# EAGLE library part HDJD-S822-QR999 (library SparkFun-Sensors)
Avago RGB color sensor, analog out

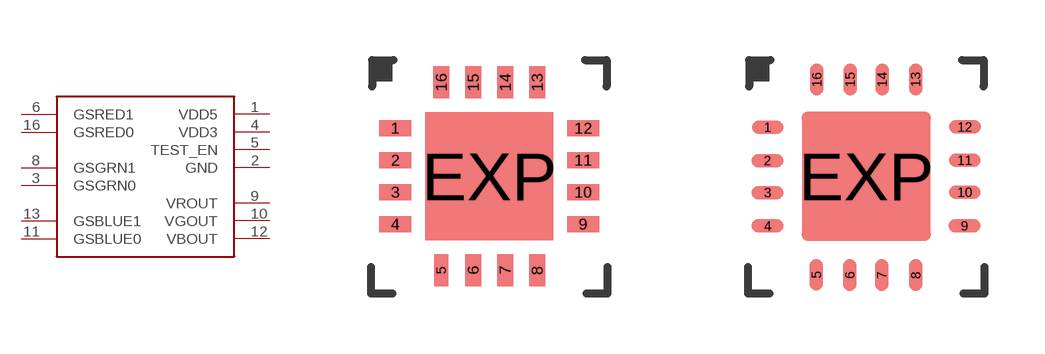
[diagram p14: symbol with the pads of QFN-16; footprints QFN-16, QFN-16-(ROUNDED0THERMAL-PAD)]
Designator prefix -

## HDJD-S822-QR999  [QFN-16]
1  VDD5
2  GND
3  GSGRN0
4  VDD3
5  TEST_EN
6  GSRED1
8  GSGRN1
9  VROUT
10  VGOUT
11  GSBLUE0
12  VBOUT
13  GSBLUE1
16  GSRED0

## HDJD-S822-QR999WITHPIC  [QFN-16-(ROUNDED0THERMAL-PAD)]
Pads as for QFN-16

## Footprint QFN-16 (pad centres in mm)
smd 0.8 x 0.4: 1 -2.35,1.2; 2 -2.35,0.4; 3 -2.35,-0.4; 4 -2.35,-1.2; 9 2.35,-1.2; 10 2.35,-0.4; 11 2.35,0.4; 12 2.35,1.2
smd 0.35 x 0.8: 5 -1.2,-2.35
smd 0.4 x 0.8: 6 -0.4,-2.35; 7 0.4,-2.35; 8 1.2,-2.35; 13 1.2,2.35; 14 0.4,2.35; 15 -0.4,2.35; 16 -1.2,2.35
smd 3.19 x 3.19: EXP 0,0

## Footprint QFN-16-(ROUNDED0THERMAL-PAD) (pad centres in mm)
smd 0.8 x 0.343: 1 -2.464,1.225; 2 -2.467,0.391; 3 -2.467,-0.409; 4 -2.467,-1.243; 9 2.458,-1.241; 10 2.463,-0.4; 11 2.463,0.4; 12 2.467,1.232
smd 0.343 x 0.8: 5 -1.247,-2.464; 6 -0.411,-2.466; 7 0.389,-2.466; 8 1.239,-2.472; 13 1.233,2.421; 14 0.396,2.418; 15 -0.404,2.418; 16 -1.236,2.418
smd 3.23 x 3.23: EXP 0,0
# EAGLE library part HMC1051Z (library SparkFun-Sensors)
Honeywell 1-axis magnetometer

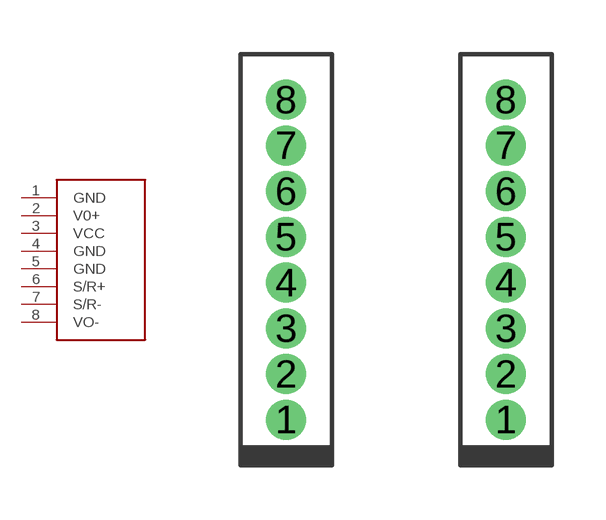
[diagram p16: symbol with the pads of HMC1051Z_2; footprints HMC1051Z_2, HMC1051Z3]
Designator prefix -

## HMC1051Z2  [HMC1051Z_2]
1  GND
2  V0+
3  VCC
4  GND
5  GND
6  S/R+
7  S/R-
8  VO-

## HMC1051Z  [HMC1051Z3]
Pads as for HMC1051Z_2

## Footprint HMC1051Z_2 (pad centres in mm)
drill 0.6 pad 0.914: 1 0,0; 2 0,1.27; 3 0,2.54; 4 0,3.81; 5 0,5.08; 6 0,6.35; 7 0,7.62; 8 0,8.89

## Footprint HMC1051Z3 (pad centres in mm)
drill 0.6 pad 0.914: 1 0,0; 2 0,1.27; 3 0,2.54; 4 0,3.81; 5 0,5.08; 6 0,6.35; 7 0,7.62; 8 0,8.89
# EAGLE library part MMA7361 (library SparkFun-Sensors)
3-axis 1.5/6g analog output accelerometer IC-09489

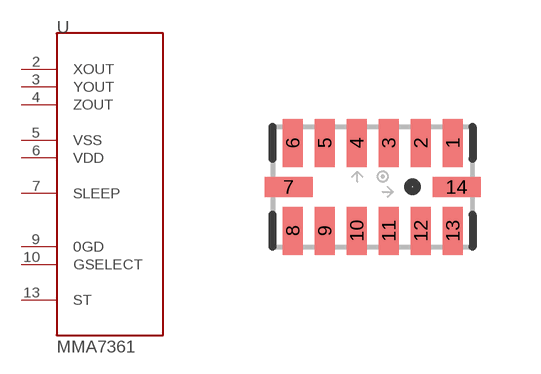
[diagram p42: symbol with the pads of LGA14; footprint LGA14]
Designator prefix U

## MMA7361 (PROD_ID: IC-09489; VALUE: IC-09489)  [LGA14]
2  XOUT
3  YOUT
4  ZOUT
5  VSS
6  VDD
7  SLEEP
9  0GD
10  GSELECT
13  ST

## Footprint LGA14 (pad centres in mm)
smd 0.5 x 1.2: 1 2,1.1; 2 1.2,1.1; 3 0.4,1.1; 4 -0.4,1.1; 5 -1.2,1.1; 6 -2,1.1; 8 -2,-1.1; 9 -1.2,-1.1; 10 -0.4,-1.1; 11 0.4,-1.1; 12 1.2,-1.1; 13 2,-1.1
smd 1.2 x 0.5: 7 -2.1,0; 14 2.1,0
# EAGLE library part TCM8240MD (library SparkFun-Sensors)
1.3MP color image sensor

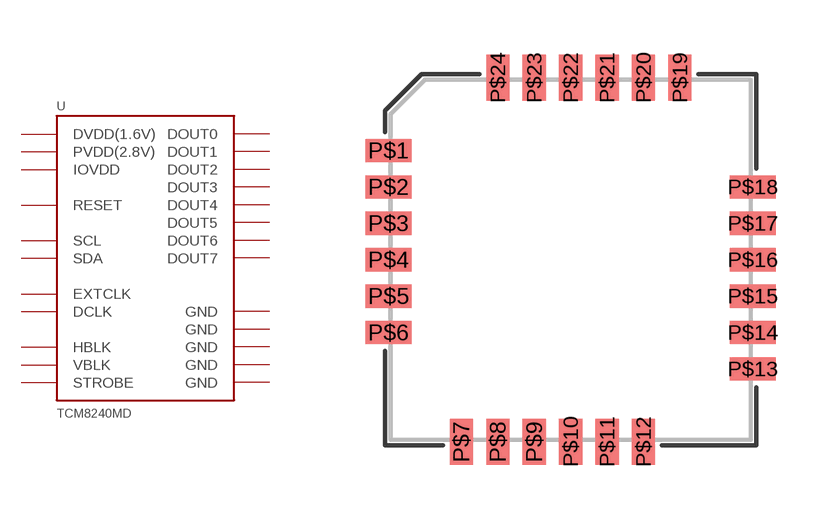
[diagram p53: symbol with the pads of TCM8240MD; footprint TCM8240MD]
Designator prefix -

## TCM8240MD  [TCM8240MD]
P$1  DOUT3
P$2  DOUT2
P$3  DOUT1
P$4  DOUT0
P$5  GND
P$6  PVDD(2.8V)
P$7  RESET
P$8  SCL
P$9  GND
P$10  SDA
P$11  GND
P$12  DVDD(1.6V)
P$13  EXTCLK
P$14  STROBE
P$15  HBLK
P$16  VBLK
P$17  GND
P$18  IOVDD
P$19  DCLK
P$20  GND
P$21  DOUT7
P$22  DOUT6
P$23  DOUT5
P$24  DOUT4

## Footprint TCM8240MD (pad centres in mm)
smd 1.27 x 0.635: P$1 -5,3; P$2 -5,2; P$3 -5,1; P$4 -5,0; P$5 -5,-1; P$6 -5,-2; P$13 5,-3; P$14 5,-2; P$15 5,-1; P$16 5,0; P$17 5,1; P$18 5,2
smd 0.635 x 1.27: P$7 -3,-5; P$8 -2,-5; P$9 -1,-5; P$10 0,-5; P$11 1,-5; P$12 2,-5; P$19 3,5; P$20 2,5; P$21 1,5; P$22 0,5; P$23 -1,5; P$24 -2,5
